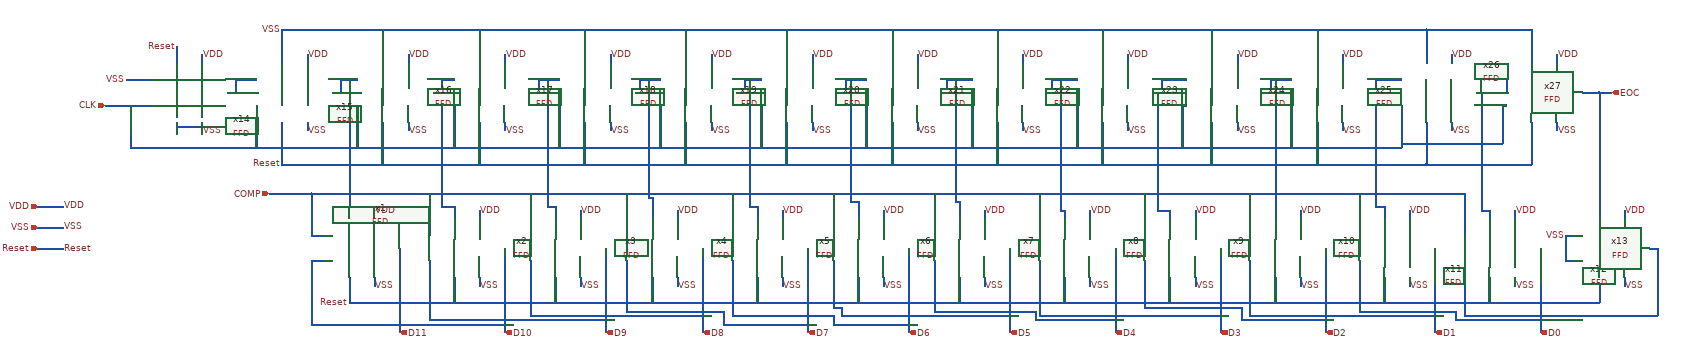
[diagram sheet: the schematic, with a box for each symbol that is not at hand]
v {xschem version=3.4.6 file_version=1.2}
G {}
K {}
V {}
S {}
E {}
N -1280 -350 -1260 -350 {lab=#net1}
N -1260 -380 -1260 -350 {lab=#net1}
N -1260 -380 -1210 -380 {lab=#net1}
N -990 -380 -990 -50 {lab=#net2}
N -1030 -350 -1010 -350 {lab=#net2}
N -1010 -380 -1010 -350 {lab=#net2}
N -1010 -380 -970 -380 {lab=#net2}
N -790 -350 -770 -350 {lab=#net3}
N -770 -380 -770 -350 {lab=#net3}
N -770 -380 -740 -380 {lab=#net3}
N -500 -80 -500 -50 {lab=#net4}
N -520 -80 -500 -80 {lab=#net4}
N -520 -350 -520 -80 {lab=#net4}
N -560 -350 -540 -350 {lab=#net4}
N -540 -380 -540 -350 {lab=#net4}
N -540 -380 -490 -380 {lab=#net4}
N -270 -100 -270 -50 {lab=#net5}
N -280 -100 -270 -100 {lab=#net5}
N -280 -380 -280 -100 {lab=#net5}
N -310 -350 -300 -350 {lab=#net5}
N -300 -380 -300 -350 {lab=#net5}
N -300 -380 -250 -380 {lab=#net5}
N -20 -80 -20 -50 {lab=#net6}
N -40 -80 -20 -80 {lab=#net6}
N -40 -380 -40 -80 {lab=#net6}
N -70 -350 -50 -350 {lab=#net6}
N -50 -380 -50 -350 {lab=#net6}
N -50 -380 -10 -380 {lab=#net6}
N 220 -90 220 -50 {lab=#net7}
N 200 -90 220 -90 {lab=#net7}
N 200 -350 200 -90 {lab=#net7}
N 170 -350 190 -350 {lab=#net7}
N 190 -380 190 -350 {lab=#net7}
N 190 -380 240 -380 {lab=#net7}
N 460 -90 460 -50 {lab=#net8}
N 450 -90 460 -90 {lab=#net8}
N 450 -380 450 -90 {lab=#net8}
N 420 -350 430 -350 {lab=#net8}
N 430 -380 430 -350 {lab=#net8}
N 430 -380 490 -380 {lab=#net8}
N 710 -70 710 -50 {lab=#net9}
N 700 -70 710 -70 {lab=#net9}
N 700 -380 700 -70 {lab=#net9}
N 670 -350 680 -350 {lab=#net9}
N 680 -380 680 -350 {lab=#net9}
N 680 -380 740 -380 {lab=#net9}
N 960 -70 960 -50 {lab=#net10}
N 930 -70 960 -70 {lab=#net10}
N 930 -350 930 -70 {lab=#net10}
N 920 -350 940 -350 {lab=#net10}
N 940 -380 940 -350 {lab=#net10}
N 940 -380 1000 -380 {lab=#net10}
N 1210 -60 1210 -50 {lab=#net11}
N 1210 -380 1210 -60 {lab=#net11}
N 1200 -380 1250 -380 {lab=#net11}
N 1200 -380 1200 -350 {lab=#net11}
N 1180 -350 1200 -350 {lab=#net11}
N 1470 -80 1470 -50 {lab=#net12}
N 1450 -80 1470 -80 {lab=#net12}
N 1450 -350 1450 -80 {lab=#net12}
N 1430 -350 1450 -350 {lab=#net12}
N 1450 -380 1450 -350 {lab=#net12}
N 1450 -380 1510 -380 {lab=#net12}
N 1720 -70 1720 -50 {lab=#net13}
N 1700 -70 1720 -70 {lab=#net13}
N 1700 -350 1700 -70 {lab=#net13}
N -1570 -320 -1460 -320 {lab=CLK}
N -1510 -320 -1510 -220 {lab=CLK}
N -1510 -220 1510 -220 {lab=CLK}
N 1510 -320 1510 -220 {lab=CLK}
N 1250 -320 1250 -220 {lab=CLK}
N 740 -320 740 -220 {lab=CLK}
N 490 -320 490 -220 {lab=CLK}
N 240 -320 240 -220 {lab=CLK}
N -10 -320 -10 -220 {lab=CLK}
N -250 -320 -250 -220 {lab=CLK}
N -490 -320 -490 -220 {lab=CLK}
N -740 -320 -740 -220 {lab=CLK}
N -970 -320 -970 -220 {lab=CLK}
N -1210 -320 -1210 -220 {lab=CLK}
N -1730 -80 -1670 -80 {lab=VDD}
N -1340 -440 -1340 -420 {lab=VDD}
N -1090 -440 -1090 -420 {lab=VDD}
N -850 -440 -850 -420 {lab=VDD}
N -620 -440 -620 -420 {lab=VDD}
N -370 -440 -370 -420 {lab=VDD}
N -130 -440 -130 -420 {lab=VDD}
N 110 -440 110 -420 {lab=VDD}
N 360 -440 360 -420 {lab=VDD}
N 610 -440 610 -420 {lab=VDD}
N 860 -440 860 -420 {lab=VDD}
N 1120 -440 1120 -420 {lab=VDD}
N 1370 -440 1370 -420 {lab=VDD}
N 1630 -440 1630 -420 {lab=VDD}
N -930 -70 -930 -50 {lab=VDD}
N -680 -70 -680 -50 {lab=VDD}
N -440 -70 -440 -50 {lab=VDD}
N -210 -70 -210 -50 {lab=VDD}
N 40 -70 40 -50 {lab=VDD}
N 280 -70 280 -50 {lab=VDD}
N 520 -70 520 -50 {lab=VDD}
N 770 -60 770 -50 {lab=VDD}
N 770 -70 770 -60 {lab=VDD}
N 1020 -70 1020 -50 {lab=VDD}
N 1270 -70 1270 -50 {lab=VDD}
N 1530 -70 1530 -50 {lab=VDD}
N 1780 -70 1780 -50 {lab=VDD}
N 2040 -70 2040 -50 {lab=VDD}
N -1340 -280 -1340 -260 {lab=VSS}
N -1090 -280 -1090 -260 {lab=VSS}
N -850 -280 -850 -260 {lab=VSS}
N -620 -280 -620 -260 {lab=VSS}
N -370 -280 -370 -260 {lab=VSS}
N -130 -280 -130 -260 {lab=VSS}
N 110 -280 110 -260 {lab=VSS}
N 360 -280 360 -260 {lab=VSS}
N 860 -280 860 -260 {lab=VSS}
N 610 -280 610 -260 {lab=VSS}
N 1120 -280 1120 -260 {lab=VSS}
N 1630 -280 1630 -260 {lab=VSS}
N 1370 -280 1370 -260 {lab=VSS}
N 2040 90 2040 110 {lab=VSS}
N 1780 90 1780 110 {lab=VSS}
N 1530 90 1530 110 {lab=VSS}
N 1270 90 1270 110 {lab=VSS}
N 1020 90 1020 110 {lab=VSS}
N 770 90 770 110 {lab=VSS}
N 520 90 520 110 {lab=VSS}
N 280 90 280 110 {lab=VSS}
N 40 90 40 110 {lab=VSS}
N -210 90 -210 110 {lab=VSS}
N -440 90 -440 110 {lab=VSS}
N -680 90 -680 110 {lab=VSS}
N -930 90 -930 110 {lab=VSS}
N -1730 -30 -1670 -30 {lab=VSS}
N -1180 -110 -1120 -110 {lab=COMP}
N -1120 -110 -1080 -110 {lab=COMP}
N -1080 -110 -1080 -10 {lab=COMP}
N -1080 -10 -1050 -10 {lab=COMP}
N -1080 -110 1660 -110 {lab=COMP}
N 1660 -110 1660 -10 {lab=COMP}
N 1410 -110 1410 -10 {lab=COMP}
N 1150 -110 1150 -10 {lab=COMP}
N 900 -110 900 -10 {lab=COMP}
N 650 -110 650 -10 {lab=COMP}
N 400 -110 400 -10 {lab=COMP}
N 160 -110 160 -10 {lab=COMP}
N -80 -110 -80 -10 {lab=COMP}
N -330 -110 -330 -10 {lab=COMP}
N -560 -110 -560 -10 {lab=COMP}
N -800 -110 -800 -10 {lab=COMP}
N -870 20 -870 220 {lab=D11}
N -620 20 -620 220 {lab=D10}
N -380 20 -380 220 {lab=D9}
N -150 20 -150 220 {lab=D8}
N 100 20 100 220 {lab=D7}
N 340 20 340 220 {lab=D6}
N 580 20 580 220 {lab=D5}
N 830 20 830 220 {lab=D4}
N 1080 20 1080 220 {lab=D3}
N 1330 20 1330 220 {lab=D2}
N 1590 20 1590 220 {lab=D1}
N 1840 20 1840 220 {lab=D0}
N -1080 50 -1050 50 {lab=D10}
N -1080 50 -1080 180 {lab=D10}
N -1080 200 -620 200 {lab=D10}
N -800 50 -800 170 {lab=D9}
N -800 190 -380 190 {lab=D9}
N -1080 180 -1080 200 {lab=D10}
N -800 170 -800 190 {lab=D9}
N -560 50 -560 180 {lab=D8}
N -560 180 -150 180 {lab=D8}
N -330 50 -330 170 {lab=D7}
N -80 50 -80 160 {lab=D6}
N -330 170 -100 170 {lab=D7}
N -100 170 -100 200 {lab=D7}
N -100 200 100 200 {lab=D7}
N -80 160 -80 180 {lab=D6}
N -80 180 160 180 {lab=D6}
N 160 180 160 200 {lab=D6}
N 160 200 340 200 {lab=D6}
N 160 50 160 160 {lab=D5}
N 160 160 180 160 {lab=D5}
N 180 160 180 180 {lab=D5}
N 180 180 580 180 {lab=D5}
N 400 50 400 170 {lab=D4}
N 400 170 640 170 {lab=D4}
N 640 170 640 190 {lab=D4}
N 640 190 830 190 {lab=D4}
N 650 50 650 180 {lab=D3}
N 650 180 1080 180 {lab=D3}
N 900 50 900 160 {lab=D2}
N 900 160 1130 160 {lab=D2}
N 1130 160 1130 190 {lab=D2}
N 1130 190 1330 190 {lab=D2}
N 1150 50 1150 180 {lab=D1}
N 1150 180 1590 180 {lab=D1}
N 1410 50 1410 170 {lab=D0}
N 1410 170 1640 170 {lab=D0}
N 1640 170 1640 190 {lab=D0}
N 1640 190 1840 190 {lab=D0}
N 1660 50 1660 180 {lab=#net14}
N 1660 180 2120 180 {lab=#net14}
N 2120 20 2120 180 {lab=#net14}
N 2100 20 2120 20 {lab=#net14}
N -1730 20 -1670 20 {lab=Reset}
N -990 90 -990 140 {lab=Reset}
N -990 140 -990 150 {lab=Reset}
N -990 150 1980 150 {lab=Reset}
N 1980 90 1980 150 {lab=Reset}
N 1720 90 1720 150 {lab=Reset}
N 1470 90 1470 150 {lab=Reset}
N 220 90 220 150 {lab=Reset}
N 710 90 710 150 {lab=Reset}
N 460 90 460 150 {lab=Reset}
N -20 90 -20 150 {lab=Reset}
N -270 90 -270 150 {lab=Reset}
N -500 90 -500 150 {lab=Reset}
N 1210 90 1210 150 {lab=Reset}
N 960 90 960 150 {lab=Reset}
N -740 90 -740 150 {lab=Reset}
N -1150 -280 -1150 -180 {lab=Reset}
N -1150 -180 1570 -180 {lab=Reset}
N 1570 -280 1570 -180 {lab=Reset}
N 1310 -280 1310 -180 {lab=Reset}
N 1060 -280 1060 -180 {lab=Reset}
N 800 -280 800 -180 {lab=Reset}
N 550 -280 550 -180 {lab=Reset}
N 300 -280 300 -180 {lab=Reset}
N 50 -280 50 -180 {lab=Reset}
N -190 -280 -190 -180 {lab=Reset}
N -430 -280 -430 -180 {lab=Reset}
N -680 -280 -680 -180 {lab=Reset}
N -910 -280 -910 -180 {lab=Reset}
N -1400 -460 -1400 -420 {lab=Reset}
N -1520 -380 -1460 -380 {lab=VSS}
N 1690 -350 1710 -350 {lab=#net13}
N 1710 -350 1730 -350 {lab=#net13}
N 1980 -350 1980 -50 {lab=EOC}
N 1900 -10 1920 -10 {lab=VSS}
N 1900 -10 1900 50 {lab=VSS}
N 1900 50 1920 50 {lab=VSS}
N -1400 -280 -1400 -270 {lab=VSS}
N -1400 -270 -1340 -270 {lab=VSS}
N -1150 -500 -1150 -420 {lab=VSS}
N -1150 -500 1570 -500 {lab=VSS}
N 1570 -500 1570 -420 {lab=VSS}
N 1310 -500 1310 -420 {lab=VSS}
N 1060 -500 1060 -420 {lab=VSS}
N 800 -500 800 -420 {lab=VSS}
N 550 -500 550 -420 {lab=VSS}
N 300 -500 300 -420 {lab=VSS}
N 50 -500 50 -420 {lab=VSS}
N -190 -500 -190 -420 {lab=VSS}
N -430 -500 -430 -420 {lab=VSS}
N -680 -500 -680 -420 {lab=VSS}
N -910 -500 -910 -420 {lab=VSS}
N 1730 -350 1760 -350 {lab=#net13}
N 990 -320 1000 -320 {lab=CLK}
N 990 -320 990 -220 {lab=CLK}
N 1880 -440 1880 -420 {lab=VDD}
N 1880 -280 1880 -260 {lab=VSS}
N 1940 -350 1960 -350 {lab=EOC}
N 1960 -350 1980 -350 {lab=EOC}
N 1980 -350 2010 -350 {lab=EOC}
N 1760 -380 1760 -350 {lab=#net13}
N 1510 -230 1750 -230 {lab=CLK}
N 1750 -320 1750 -230 {lab=CLK}
N 1750 -320 1760 -320 {lab=CLK}
N 1570 -180 1820 -180 {lab=Reset}
N 1820 -280 1820 -180 {lab=Reset}
N 1570 -500 1820 -500 {lab=VSS}
N 1820 -500 1820 -420 {lab=VSS}
N -520 -380 -520 -350 {lab=#net4}
N -740 -80 -740 -50 {lab=#net3}
N -770 -80 -740 -80 {lab=#net3}
N -770 -350 -770 -80 {lab=#net3}
N 200 -380 200 -350 {lab=#net7}
C {project/FFD.sym} -900 20 0 0 {name=x1}
C {project/FFD.sym} -650 20 0 0 {name=x2}
C {project/FFD.sym} -410 20 0 0 {name=x3}
C {project/FFD.sym} -180 20 0 0 {name=x4}
C {project/FFD.sym} 70 20 0 0 {name=x5}
C {project/FFD.sym} 310 20 0 0 {name=x6}
C {project/FFD.sym} 550 20 0 0 {name=x7}
C {project/FFD.sym} 800 20 0 0 {name=x8}
C {project/FFD.sym} 1050 20 0 0 {name=x9}
C {project/FFD.sym} 1300 20 0 0 {name=x10}
C {project/FFD.sym} 1560 20 0 0 {name=x11}
C {project/FFD.sym} 1810 20 0 0 {name=x12}
C {project/FFD.sym} 2070 20 0 0 {name=x13}
C {project/FFD.sym} -1310 -350 0 0 {name=x14}
C {project/FFD.sym} -1060 -350 0 0 {name=x15}
C {project/FFD.sym} -820 -350 0 0 {name=x16}
C {project/FFD.sym} -590 -350 0 0 {name=x17}
C {project/FFD.sym} -340 -350 0 0 {name=x18}
C {project/FFD.sym} -100 -350 0 0 {name=x19}
C {project/FFD.sym} 140 -350 0 0 {name=x20}
C {project/FFD.sym} 390 -350 0 0 {name=x21}
C {project/FFD.sym} 640 -350 0 0 {name=x22}
C {project/FFD.sym} 890 -350 0 0 {name=x23}
C {project/FFD.sym} 1150 -350 0 0 {name=x24}
C {project/FFD.sym} 1400 -350 0 0 {name=x25}
C {project/FFD.sym} 1660 -350 0 0 {name=x26}
C {devices/ipin.sym} -1570 -320 0 0 {name=p1 lab=CLK}
C {devices/ipin.sym} -1730 -80 0 0 {name=p2 lab=VDD}
C {devices/ipin.sym} -1730 -30 0 0 {name=p3 lab=VSS}
C {devices/ipin.sym} -1180 -110 0 0 {name=p4 lab=COMP}
C {devices/lab_pin.sym} -1670 -80 2 0 {name=p5 sig_type=std_logic lab=VDD}
C {devices/lab_pin.sym} -1340 -440 2 0 {name=p6 sig_type=std_logic lab=VDD}
C {devices/lab_pin.sym} -1090 -440 2 0 {name=p7 sig_type=std_logic lab=VDD}
C {devices/lab_pin.sym} -850 -440 2 0 {name=p8 sig_type=std_logic lab=VDD}
C {devices/lab_pin.sym} -620 -440 2 0 {name=p9 sig_type=std_logic lab=VDD}
C {devices/lab_pin.sym} -370 -440 2 0 {name=p10 sig_type=std_logic lab=VDD}
C {devices/lab_pin.sym} -130 -440 2 0 {name=p11 sig_type=std_logic lab=VDD}
C {devices/lab_pin.sym} 110 -440 2 0 {name=p12 sig_type=std_logic lab=VDD}
C {devices/lab_pin.sym} 360 -440 2 0 {name=p13 sig_type=std_logic lab=VDD}
C {devices/lab_pin.sym} 610 -440 2 0 {name=p14 sig_type=std_logic lab=VDD}
C {devices/lab_pin.sym} 860 -440 2 0 {name=p15 sig_type=std_logic lab=VDD}
C {devices/lab_pin.sym} 1120 -440 2 0 {name=p16 sig_type=std_logic lab=VDD}
C {devices/lab_pin.sym} 1370 -440 2 0 {name=p17 sig_type=std_logic lab=VDD}
C {devices/lab_pin.sym} 1630 -440 2 0 {name=p18 sig_type=std_logic lab=VDD}
C {devices/lab_pin.sym} -930 -70 2 0 {name=p19 sig_type=std_logic lab=VDD}
C {devices/lab_pin.sym} -680 -70 2 0 {name=p20 sig_type=std_logic lab=VDD}
C {devices/lab_pin.sym} -440 -70 2 0 {name=p21 sig_type=std_logic lab=VDD}
C {devices/lab_pin.sym} -210 -70 2 0 {name=p22 sig_type=std_logic lab=VDD}
C {devices/lab_pin.sym} 40 -70 2 0 {name=p23 sig_type=std_logic lab=VDD}
C {devices/lab_pin.sym} 280 -70 2 0 {name=p24 sig_type=std_logic lab=VDD}
C {devices/lab_pin.sym} 520 -70 2 0 {name=p25 sig_type=std_logic lab=VDD}
C {devices/lab_pin.sym} 770 -70 2 0 {name=p26 sig_type=std_logic lab=VDD}
C {devices/lab_pin.sym} 1020 -70 2 0 {name=p27 sig_type=std_logic lab=VDD}
C {devices/lab_pin.sym} 1270 -70 2 0 {name=p28 sig_type=std_logic lab=VDD}
C {devices/lab_pin.sym} 1530 -70 2 0 {name=p29 sig_type=std_logic lab=VDD}
C {devices/lab_pin.sym} 1780 -70 2 0 {name=p30 sig_type=std_logic lab=VDD}
C {devices/lab_pin.sym} 2040 -70 2 0 {name=p31 sig_type=std_logic lab=VDD}
C {devices/lab_pin.sym} -1670 -30 2 0 {name=p32 sig_type=std_logic lab=VSS}
C {devices/lab_pin.sym} -1340 -260 2 0 {name=p33 sig_type=std_logic lab=VSS}
C {devices/lab_pin.sym} -1090 -260 2 0 {name=p34 sig_type=std_logic lab=VSS}
C {devices/lab_pin.sym} -850 -260 2 0 {name=p35 sig_type=std_logic lab=VSS}
C {devices/lab_pin.sym} -620 -260 2 0 {name=p36 sig_type=std_logic lab=VSS}
C {devices/lab_pin.sym} -370 -260 2 0 {name=p37 sig_type=std_logic lab=VSS}
C {devices/lab_pin.sym} -130 -260 2 0 {name=p38 sig_type=std_logic lab=VSS}
C {devices/lab_pin.sym} 110 -260 2 0 {name=p39 sig_type=std_logic lab=VSS}
C {devices/lab_pin.sym} 360 -260 2 0 {name=p40 sig_type=std_logic lab=VSS}
C {devices/lab_pin.sym} 610 -260 2 0 {name=p41 sig_type=std_logic lab=VSS}
C {devices/lab_pin.sym} 860 -260 2 0 {name=p42 sig_type=std_logic lab=VSS}
C {devices/lab_pin.sym} 1120 -260 2 0 {name=p43 sig_type=std_logic lab=VSS}
C {devices/lab_pin.sym} 1370 -260 2 0 {name=p44 sig_type=std_logic lab=VSS}
C {devices/lab_pin.sym} 1630 -260 2 0 {name=p45 sig_type=std_logic lab=VSS}
C {devices/lab_pin.sym} -930 110 2 0 {name=p46 sig_type=std_logic lab=VSS}
C {devices/lab_pin.sym} -680 110 2 0 {name=p47 sig_type=std_logic lab=VSS}
C {devices/lab_pin.sym} -440 110 2 0 {name=p48 sig_type=std_logic lab=VSS}
C {devices/lab_pin.sym} -210 110 2 0 {name=p49 sig_type=std_logic lab=VSS}
C {devices/lab_pin.sym} 40 110 2 0 {name=p50 sig_type=std_logic lab=VSS}
C {devices/lab_pin.sym} 280 110 2 0 {name=p51 sig_type=std_logic lab=VSS}
C {devices/lab_pin.sym} 520 110 2 0 {name=p52 sig_type=std_logic lab=VSS}
C {devices/lab_pin.sym} 770 110 2 0 {name=p53 sig_type=std_logic lab=VSS}
C {devices/lab_pin.sym} 1020 110 2 0 {name=p54 sig_type=std_logic lab=VSS}
C {devices/lab_pin.sym} 1270 110 2 0 {name=p55 sig_type=std_logic lab=VSS}
C {devices/lab_pin.sym} 1530 110 2 0 {name=p56 sig_type=std_logic lab=VSS}
C {devices/lab_pin.sym} 1780 110 2 0 {name=p57 sig_type=std_logic lab=VSS}
C {devices/lab_pin.sym} 2040 110 2 0 {name=p58 sig_type=std_logic lab=VSS}
C {devices/opin.sym} -870 220 0 0 {name=p59 lab=D11}
C {devices/opin.sym} -620 220 0 0 {name=p60 lab=D10}
C {devices/opin.sym} -380 220 0 0 {name=p61 lab=D9}
C {devices/opin.sym} -150 220 0 0 {name=p62 lab=D8}
C {devices/opin.sym} 100 220 0 0 {name=p63 lab=D7}
C {devices/opin.sym} 340 220 0 0 {name=p64 lab=D6}
C {devices/opin.sym} 580 220 0 0 {name=p65 lab=D5}
C {devices/opin.sym} 830 220 0 0 {name=p66 lab=D4}
C {devices/opin.sym} 1080 220 0 0 {name=p67 lab=D3}
C {devices/opin.sym} 1330 220 0 0 {name=p68 lab=D2}
C {devices/opin.sym} 1590 220 0 0 {name=p69 lab=D1}
C {devices/opin.sym} 1840 220 0 0 {name=p70 lab=D0}
C {devices/ipin.sym} -1730 20 0 0 {name=p71 lab=Reset}
C {devices/lab_pin.sym} -1670 20 2 0 {name=p72 sig_type=std_logic lab=Reset}
C {devices/lab_pin.sym} -990 150 0 0 {name=p73 sig_type=std_logic lab=Reset}
C {devices/lab_pin.sym} -1150 -180 0 0 {name=p74 sig_type=std_logic lab=Reset}
C {devices/lab_pin.sym} -1400 -460 0 0 {name=p75 sig_type=std_logic lab=Reset}
C {devices/lab_pin.sym} -1520 -380 0 0 {name=p76 sig_type=std_logic lab=VSS}
C {devices/lab_pin.sym} 1900 -10 0 0 {name=p77 sig_type=std_logic lab=VSS}
C {devices/lab_pin.sym} -1150 -500 0 0 {name=p78 sig_type=std_logic lab=VSS}
C {devices/opin.sym} 2010 -350 0 0 {name=p79 lab=EOC}
C {project/FFD.sym} 1910 -350 0 0 {name=x27}
C {devices/lab_pin.sym} 1880 -440 2 0 {name=p80 sig_type=std_logic lab=VDD}
C {devices/lab_pin.sym} 1880 -260 2 0 {name=p81 sig_type=std_logic lab=VSS}
